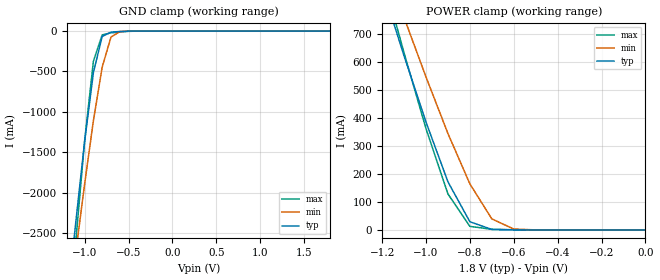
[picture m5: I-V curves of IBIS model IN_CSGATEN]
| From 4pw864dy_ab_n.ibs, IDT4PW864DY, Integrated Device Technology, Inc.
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|   Model IN_CSGATEN
[Model]   IN_CSGATEN
Model_type   Input
Vinl =  0.000V
Vinh =  1.80000V
C_comp   1.750000pF   1.75000pF   1.75000pF
[Temperature Range]   25.00000   0.11000k   0.000
[Voltage Range]   1.80000V   1.70000V   1.90000V
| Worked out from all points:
|   GND clamp passes 1 mA (typ) near -0.49 V on its own axis
|   POWER clamp passes 1 mA (typ) near -0.65 V on its own axis
[GND_clamp]
| voltage   I(typ)   I(min)   I(max)
-1.8V     -10.01A    -9.038A    -12.29A
-1.2V     -3.404A    -3.6A      -3.912A
-1.1V     -2.358A    -2.733A    -2.593A
-1V       -1.367A    -1.894A    -1.358A
-900mV    -513.3mA   -1.109A    -373mA
-800mV    -66.28mA   -445.9mA   -47.02mA
-700mV    -13.26mA   -74.72mA   -21.99mA
-600mV    -4.883mA   -6.553mA   -10.82mA
-300mV    -13.3uA    -7.047uA   -54.05uA
1.8V      1.004nA    10.93nA    727.1pA
[POWER_clamp]
| voltage   I(typ)   I(min)   I(max)
-1.8V     2.418A     2.339A     2.707A
-1.2V     869mA      977.4mA    916.7mA
-1.1V     622.1mA    758.9mA    632.6mA
-1V       385.4mA    546.5mA    362mA
-900mV    172mA      344.5mA    128.7mA
-800mV    29.34mA    164.6mA    12.9mA
-700mV    1.853mA    39.55mA    2.312mA
-600mV    274.2uA    3.273mA    719.3uA
-500mV    42.16uA    215.3uA    140.6uA
0V        1.004nA    656.2pA    852pA
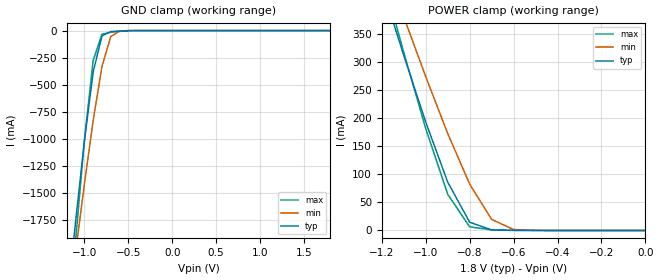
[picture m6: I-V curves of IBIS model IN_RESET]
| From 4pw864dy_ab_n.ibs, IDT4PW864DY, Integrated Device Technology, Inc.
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|   Model IN_RESET
[Model]   IN_RESET
Model_type   Input
Vinl =  0.59500V
Vinh =  1.23500V
C_comp   1.750000pF   1.75000pF   1.75000pF
[Temperature Range]   25.00000   0.11000k   0.000
[Voltage Range]   1.80000V   1.70000V   1.90000V
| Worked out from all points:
|   GND clamp passes 1 mA (typ) near -0.51 V on its own axis
|   POWER clamp passes 1 mA (typ) near -0.70 V on its own axis
[GND_clamp]
| voltage   I(typ)   I(min)   I(max)
-1.8V     -7.508A    -6.776A    -9.219A
-1.2V     -2.551A    -2.699A    -2.932A
-1.1V     -1.768A    -2.048A    -1.943A
-1V       -1.024A    -1.42A     -1.017A
-900mV    -384.2mA   -831.6mA   -278.7mA
-800mV    -49.06mA   -333.9mA   -34.47mA
-700mV    -9.463mA   -55.73mA   -15.88mA
-600mV    -3.334mA   -4.731mA   -7.676mA
-400mV    -53.55uA   -34.01uA   -241.1uA
1.8V      26.95pA    5.248nA    -19.88pA
[POWER_clamp]
| voltage   I(typ)   I(min)   I(max)
-1.8V     1.209A     1.169A     1.353A
-1.2V     434.4mA    488.7mA    458.3mA
-1.1V     311.1mA    379.5mA    316.3mA
-1V       192.7mA    273.3mA    181mA
-900mV    85.9mA     172.3mA    64.37mA
-800mV    14.67mA    82.28mA    6.452mA
-700mV    926.3uA    19.77mA    1.156mA
-600mV    137.1uA    1.636mA    359.6uA
-500mV    21.08uA    107.7uA    70.28uA
0V        26.95pA    124.4pA    8.261pA
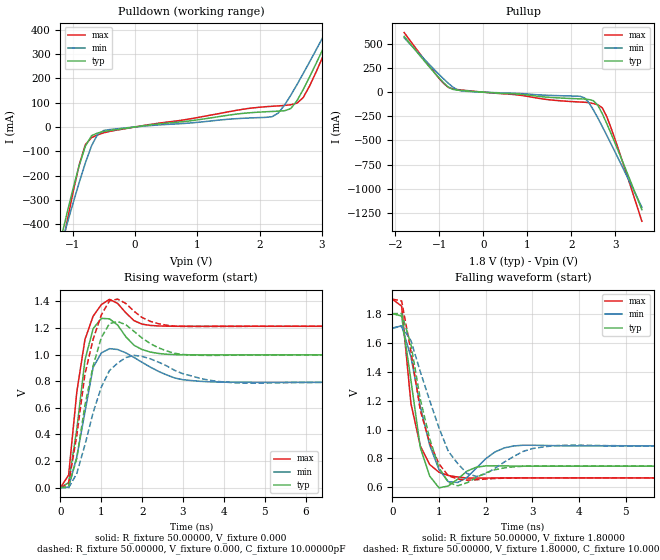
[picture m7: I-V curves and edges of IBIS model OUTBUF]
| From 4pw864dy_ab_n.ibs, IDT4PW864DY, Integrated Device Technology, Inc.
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|   Model OUTBUF
[Model]   OUTBUF
Model_type   Output
Polarity   Inverting
Vmeas =  0.90000V
C_comp   6.50000pF   5.40000pF   8.10000pF
[Temperature Range]   25.00000   0.11000k   0.000
[Voltage Range]   1.80000V   1.70000V   1.90000V
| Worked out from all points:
|   slope of the pulldown table from 0 to 0.27 V, typ, clamps not added: 29.7 ohm
|   slope of the pullup table from 0 to 0.27 V, typ, clamps not added: 35.5 ohm
|   rising waveform, R_fixture 50.00000, V_fixture 0.000: 20-80 % time 257ps typ, 302ps min, 280ps max; typ from 0 V to 0.997 V
|   rising waveform, R_fixture 50.00000, V_fixture 0.000, C_fixture 10.00000pF: 20-80 % time 340ps typ, 424ps min, 371ps max; typ from 0 V to 0.997 V
|   falling waveform, R_fixture 50.00000, V_fixture 1.80000: 20-80 % time 278ps typ, 316ps min, 323ps max; typ from 1.8 V to 0.747 V
|   falling waveform, R_fixture 50.00000, V_fixture 1.80000, C_fixture 10.00000pF: 20-80 % time 388ps typ, 488ps min, 462ps max; typ from 1.8 V to 0.747 V
[Pulldown]
| voltage   I(typ)   I(min)   I(max)
-1.8V     -1.143A    -1.055A    -1.369A
-1.2V     -468.2mA   -494.8mA   -530.4mA
-1.1V     -360.3mA   -404.2mA   -397.3mA
-900mV    -159.4mA   -229.2mA   -157.4mA
-700mV    -35.92mA   -76.98mA   -43.85mA
-500mV    -18.76mA   -14.23mA   -23.74mA
2.2V      63.59mA    42.02mA    84.92mA
2.5V      75.54mA    130.3mA    91.16mA
2.7V      153.8mA    219.6mA    120.8mA
3.1V      365.6mA    409.3mA    339.1mA
3.2V      420.6mA    457.7mA    399.4mA
3.6V      644mA      653.4mA    645.3mA
[Pullup]
| voltage   I(typ)   I(min)   I(max)
-1.8V     578.2mA    563.7mA    617.9mA
-1.1V     194.8mA    226.9mA    195.6mA
-800mV    54.3mA     93.41mA    50.68mA
-500mV    17.9mA     13.27mA    22.79mA
2.2V      -69.13mA   -43.15mA   -102mA
2.3V      -71.41mA   -59.75mA   -104.4mA
2.5V      -88.66mA   -184.8mA   -118mA
2.6V      -135.6mA   -267.6mA   -130.6mA
2.7V      -221.8mA   -354.8mA   -161.5mA
2.8V      -322.5mA   -444.4mA   -250.6mA
3V        -538.3mA   -627.8mA   -500.9mA
3.6V      -1.218A    -1.192A    -1.338A
[Ramp]
| variable   typ   min   max
dV/dt_r   1.01160/0.34057n   0.91800/0.39367n   1.08660/0.38982n
dV/dt_f   1.02281/0.38077n   0.94146/0.41536n   1.09082/0.53767n
R_load = 0.50000k
[Rising Waveform]
R_fixture = 50.00000
V_fixture = 0.000
V_fixture_min = 0.000
V_fixture_max = 0.000
| time   V(typ)   V(min)   V(max)
0s        0V         0V         0V
200ps     37.78mV    4.33mV     94.59mV
400ps     438.5mV    230.7mV    717.8mV
600ps     958.7mV    568.6mV    1.113V
800ps     1.194V     903.2mV    1.288V
1.2ns     1.268V     1.044V     1.415V
1.8ns     1.069V     978.1mV    1.254V
2.4ns     1.008V     873.3mV    1.214V
3.6ns     997.3mV    795.7mV    1.212V
10ns      997.2mV    790.9mV    1.212V
[Rising Waveform]
R_fixture = 50.00000
V_fixture = 0.000
V_fixture_min = 0.000
V_fixture_max = 0.000
C_fixture = 10.00000pF
| time   V(typ)   V(min)   V(max)
0s        0V         0V         0V
200ps     10.02mV    -1.543mV   31.6mV
400ps     219.7mV    106.5mV    390.4mV
600ps     620.6mV    322.2mV    853.5mV
1ns       1.127V     754.8mV    1.297V
1.2ns     1.232V     879.5mV    1.403V
1.8ns     1.174V     993.6mV    1.325V
3ns       1V         855.2mV    1.211V
4.4ns     995.9mV    786.3mV    1.211V
10ns      997.2mV    790.8mV    1.212V
[Falling Waveform]
R_fixture = 50.00000
V_fixture = 1.80000
V_fixture_min = 1.70000
V_fixture_max = 1.90000
| time   V(typ)   V(min)   V(max)
0s        1.8V       1.7V       1.9V
200ps     1.783V     1.716V     1.851V
400ps     1.338V     1.5V       1.179V
600ps     875.9mV    1.159V     886.3mV
800ps     679.2mV    892.7mV    758.8mV
1ns       597.2mV    723.7mV    705mV
1.4ns     657.6mV    634.6mV    672.3mV
2.2ns     749.7mV    845.3mV    665.6mV
2.8ns     747.2mV    891.4mV    665.8mV
10ns      747mV      887.1mV    665.8mV
[Falling Waveform]
R_fixture = 50.00000
V_fixture = 1.80000
V_fixture_min = 1.70000
V_fixture_max = 1.90000
C_fixture = 10.00000pF
| time   V(typ)   V(min)   V(max)
0s        1.8V       1.7V       1.9V
200ps     1.8V       1.712V     1.887V
400ps     1.587V     1.613V     1.54V
600ps     1.21V      1.399V     1.131V
800ps     937.8mV    1.201V     909.2mV
1ns       736.9mV    1.011V     763mV
1.2ns     635mV      849.5mV    680.7mV
1.8ns     669mV      676.2mV    653.2mV
3.4ns     747.6mV    886.1mV    665.9mV
10ns      747mV      887.1mV    665.8mV
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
